# Generated by FakeRAM 2.0
VERSION 5.7 ;
BUSBITCHARS "[]" ;
PROPERTYDEFINITIONS
  MACRO width INTEGER ;
  MACRO depth INTEGER ;
  MACRO banks INTEGER ;
END PROPERTYDEFINITIONS
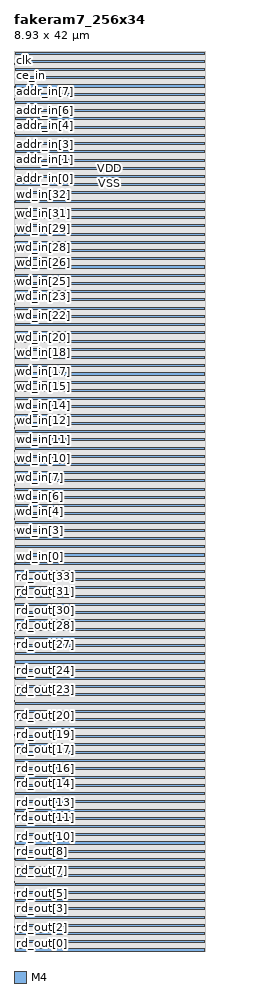
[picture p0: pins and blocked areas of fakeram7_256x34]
MACRO fakeram7_256x34
  PROPERTY width 34 ;
  PROPERTY depth 256 ;
  PROPERTY banks 2 ;
  FOREIGN fakeram7_256x34 0 0 ;
  SYMMETRY X Y R90 ;
  SIZE 8.930 BY 42.000 ;
  CLASS BLOCK ;
  PIN rd_out[0]
    DIRECTION OUTPUT ;
    USE SIGNAL ;
    SHAPE ABUTMENT ;
    PORT
      LAYER M4 ;
      RECT 0.000 0.048 0.024 0.072 ;
    END
  END rd_out[0]
  PIN rd_out[1]
    DIRECTION OUTPUT ;
    USE SIGNAL ;
    SHAPE ABUTMENT ;
    PORT
      LAYER M4 ;
      RECT 0.000 0.576 0.024 0.600 ;
    END
  END rd_out[1]
  PIN rd_out[2]
    DIRECTION OUTPUT ;
    USE SIGNAL ;
    SHAPE ABUTMENT ;
    PORT
      LAYER M4 ;
      RECT 0.000 1.104 0.024 1.128 ;
    END
  END rd_out[2]
  PIN rd_out[3]
    DIRECTION OUTPUT ;
    USE SIGNAL ;
    SHAPE ABUTMENT ;
    PORT
      LAYER M4 ;
      RECT 0.000 1.632 0.024 1.656 ;
    END
  END rd_out[3]
  PIN rd_out[4]
    DIRECTION OUTPUT ;
    USE SIGNAL ;
    SHAPE ABUTMENT ;
    PORT
      LAYER M4 ;
      RECT 0.000 2.160 0.024 2.184 ;
    END
  END rd_out[4]
  PIN rd_out[5]
    DIRECTION OUTPUT ;
    USE SIGNAL ;
    SHAPE ABUTMENT ;
    PORT
      LAYER M4 ;
      RECT 0.000 2.688 0.024 2.712 ;
    END
  END rd_out[5]
  PIN rd_out[6]
    DIRECTION OUTPUT ;
    USE SIGNAL ;
    SHAPE ABUTMENT ;
    PORT
      LAYER M4 ;
      RECT 0.000 3.216 0.024 3.240 ;
    END
  END rd_out[6]
  PIN rd_out[7]
    DIRECTION OUTPUT ;
    USE SIGNAL ;
    SHAPE ABUTMENT ;
    PORT
      LAYER M4 ;
      RECT 0.000 3.744 0.024 3.768 ;
    END
  END rd_out[7]
  PIN rd_out[8]
    DIRECTION OUTPUT ;
    USE SIGNAL ;
    SHAPE ABUTMENT ;
    PORT
      LAYER M4 ;
      RECT 0.000 4.272 0.024 4.296 ;
    END
  END rd_out[8]
  PIN rd_out[9]
    DIRECTION OUTPUT ;
    USE SIGNAL ;
    SHAPE ABUTMENT ;
    PORT
      LAYER M4 ;
      RECT 0.000 4.800 0.024 4.824 ;
    END
  END rd_out[9]
  PIN rd_out[10]
    DIRECTION OUTPUT ;
    USE SIGNAL ;
    SHAPE ABUTMENT ;
    PORT
      LAYER M4 ;
      RECT 0.000 5.328 0.024 5.352 ;
    END
  END rd_out[10]
  PIN rd_out[11]
    DIRECTION OUTPUT ;
    USE SIGNAL ;
    SHAPE ABUTMENT ;
    PORT
      LAYER M4 ;
      RECT 0.000 5.856 0.024 5.880 ;
    END
  END rd_out[11]
  PIN rd_out[12]
    DIRECTION OUTPUT ;
    USE SIGNAL ;
    SHAPE ABUTMENT ;
    PORT
      LAYER M4 ;
      RECT 0.000 6.384 0.024 6.408 ;
    END
  END rd_out[12]
  PIN rd_out[13]
    DIRECTION OUTPUT ;
    USE SIGNAL ;
    SHAPE ABUTMENT ;
    PORT
      LAYER M4 ;
      RECT 0.000 6.912 0.024 6.936 ;
    END
  END rd_out[13]
  PIN rd_out[14]
    DIRECTION OUTPUT ;
    USE SIGNAL ;
    SHAPE ABUTMENT ;
    PORT
      LAYER M4 ;
      RECT 0.000 7.440 0.024 7.464 ;
    END
  END rd_out[14]
  PIN rd_out[15]
    DIRECTION OUTPUT ;
    USE SIGNAL ;
    SHAPE ABUTMENT ;
    PORT
      LAYER M4 ;
      RECT 0.000 7.968 0.024 7.992 ;
    END
  END rd_out[15]
  PIN rd_out[16]
    DIRECTION OUTPUT ;
    USE SIGNAL ;
    SHAPE ABUTMENT ;
    PORT
      LAYER M4 ;
      RECT 0.000 8.496 0.024 8.520 ;
    END
  END rd_out[16]
  PIN rd_out[17]
    DIRECTION OUTPUT ;
    USE SIGNAL ;
    SHAPE ABUTMENT ;
    PORT
      LAYER M4 ;
      RECT 0.000 9.024 0.024 9.048 ;
    END
  END rd_out[17]
  PIN rd_out[18]
    DIRECTION OUTPUT ;
    USE SIGNAL ;
    SHAPE ABUTMENT ;
    PORT
      LAYER M4 ;
      RECT 0.000 9.552 0.024 9.576 ;
    END
  END rd_out[18]
  PIN rd_out[19]
    DIRECTION OUTPUT ;
    USE SIGNAL ;
    SHAPE ABUTMENT ;
    PORT
      LAYER M4 ;
      RECT 0.000 10.080 0.024 10.104 ;
    END
  END rd_out[19]
  PIN rd_out[20]
    DIRECTION OUTPUT ;
    USE SIGNAL ;
    SHAPE ABUTMENT ;
    PORT
      LAYER M4 ;
      RECT 0.000 10.608 0.024 10.632 ;
    END
  END rd_out[20]
  PIN rd_out[21]
    DIRECTION OUTPUT ;
    USE SIGNAL ;
    SHAPE ABUTMENT ;
    PORT
      LAYER M4 ;
      RECT 0.000 11.136 0.024 11.160 ;
    END
  END rd_out[21]
  PIN rd_out[22]
    DIRECTION OUTPUT ;
    USE SIGNAL ;
    SHAPE ABUTMENT ;
    PORT
      LAYER M4 ;
      RECT 0.000 11.664 0.024 11.688 ;
    END
  END rd_out[22]
  PIN rd_out[23]
    DIRECTION OUTPUT ;
    USE SIGNAL ;
    SHAPE ABUTMENT ;
    PORT
      LAYER M4 ;
      RECT 0.000 12.192 0.024 12.216 ;
    END
  END rd_out[23]
  PIN rd_out[24]
    DIRECTION OUTPUT ;
    USE SIGNAL ;
    SHAPE ABUTMENT ;
    PORT
      LAYER M4 ;
      RECT 0.000 12.720 0.024 12.744 ;
    END
  END rd_out[24]
  PIN rd_out[25]
    DIRECTION OUTPUT ;
    USE SIGNAL ;
    SHAPE ABUTMENT ;
    PORT
      LAYER M4 ;
      RECT 0.000 13.248 0.024 13.272 ;
    END
  END rd_out[25]
  PIN rd_out[26]
    DIRECTION OUTPUT ;
    USE SIGNAL ;
    SHAPE ABUTMENT ;
    PORT
      LAYER M4 ;
      RECT 0.000 13.776 0.024 13.800 ;
    END
  END rd_out[26]
  PIN rd_out[27]
    DIRECTION OUTPUT ;
    USE SIGNAL ;
    SHAPE ABUTMENT ;
    PORT
      LAYER M4 ;
      RECT 0.000 14.304 0.024 14.328 ;
    END
  END rd_out[27]
  PIN rd_out[28]
    DIRECTION OUTPUT ;
    USE SIGNAL ;
    SHAPE ABUTMENT ;
    PORT
      LAYER M4 ;
      RECT 0.000 14.832 0.024 14.856 ;
    END
  END rd_out[28]
  PIN rd_out[29]
    DIRECTION OUTPUT ;
    USE SIGNAL ;
    SHAPE ABUTMENT ;
    PORT
      LAYER M4 ;
      RECT 0.000 15.360 0.024 15.384 ;
    END
  END rd_out[29]
  PIN rd_out[30]
    DIRECTION OUTPUT ;
    USE SIGNAL ;
    SHAPE ABUTMENT ;
    PORT
      LAYER M4 ;
      RECT 0.000 15.888 0.024 15.912 ;
    END
  END rd_out[30]
  PIN rd_out[31]
    DIRECTION OUTPUT ;
    USE SIGNAL ;
    SHAPE ABUTMENT ;
    PORT
      LAYER M4 ;
      RECT 0.000 16.416 0.024 16.440 ;
    END
  END rd_out[31]
  PIN rd_out[32]
    DIRECTION OUTPUT ;
    USE SIGNAL ;
    SHAPE ABUTMENT ;
    PORT
      LAYER M4 ;
      RECT 0.000 16.944 0.024 16.968 ;
    END
  END rd_out[32]
  PIN rd_out[33]
    DIRECTION OUTPUT ;
    USE SIGNAL ;
    SHAPE ABUTMENT ;
    PORT
      LAYER M4 ;
      RECT 0.000 17.472 0.024 17.496 ;
    END
  END rd_out[33]
  PIN wd_in[0]
    DIRECTION INPUT ;
    USE SIGNAL ;
    SHAPE ABUTMENT ;
    PORT
      LAYER M4 ;
      RECT 0.000 18.048 0.024 18.072 ;
    END
  END wd_in[0]
  PIN wd_in[1]
    DIRECTION INPUT ;
    USE SIGNAL ;
    SHAPE ABUTMENT ;
    PORT
      LAYER M4 ;
      RECT 0.000 18.576 0.024 18.600 ;
    END
  END wd_in[1]
  PIN wd_in[2]
    DIRECTION INPUT ;
    USE SIGNAL ;
    SHAPE ABUTMENT ;
    PORT
      LAYER M4 ;
      RECT 0.000 19.104 0.024 19.128 ;
    END
  END wd_in[2]
  PIN wd_in[3]
    DIRECTION INPUT ;
    USE SIGNAL ;
    SHAPE ABUTMENT ;
    PORT
      LAYER M4 ;
      RECT 0.000 19.632 0.024 19.656 ;
    END
  END wd_in[3]
  PIN wd_in[4]
    DIRECTION INPUT ;
    USE SIGNAL ;
    SHAPE ABUTMENT ;
    PORT
      LAYER M4 ;
      RECT 0.000 20.160 0.024 20.184 ;
    END
  END wd_in[4]
  PIN wd_in[5]
    DIRECTION INPUT ;
    USE SIGNAL ;
    SHAPE ABUTMENT ;
    PORT
      LAYER M4 ;
      RECT 0.000 20.688 0.024 20.712 ;
    END
  END wd_in[5]
  PIN wd_in[6]
    DIRECTION INPUT ;
    USE SIGNAL ;
    SHAPE ABUTMENT ;
    PORT
      LAYER M4 ;
      RECT 0.000 21.216 0.024 21.240 ;
    END
  END wd_in[6]
  PIN wd_in[7]
    DIRECTION INPUT ;
    USE SIGNAL ;
    SHAPE ABUTMENT ;
    PORT
      LAYER M4 ;
      RECT 0.000 21.744 0.024 21.768 ;
    END
  END wd_in[7]
  PIN wd_in[8]
    DIRECTION INPUT ;
    USE SIGNAL ;
    SHAPE ABUTMENT ;
    PORT
      LAYER M4 ;
      RECT 0.000 22.272 0.024 22.296 ;
    END
  END wd_in[8]
  PIN wd_in[9]
    DIRECTION INPUT ;
    USE SIGNAL ;
    SHAPE ABUTMENT ;
    PORT
      LAYER M4 ;
      RECT 0.000 22.800 0.024 22.824 ;
    END
  END wd_in[9]
  PIN wd_in[10]
    DIRECTION INPUT ;
    USE SIGNAL ;
    SHAPE ABUTMENT ;
    PORT
      LAYER M4 ;
      RECT 0.000 23.328 0.024 23.352 ;
    END
  END wd_in[10]
  PIN wd_in[11]
    DIRECTION INPUT ;
    USE SIGNAL ;
    SHAPE ABUTMENT ;
    PORT
      LAYER M4 ;
      RECT 0.000 23.856 0.024 23.880 ;
    END
  END wd_in[11]
  PIN wd_in[12]
    DIRECTION INPUT ;
    USE SIGNAL ;
    SHAPE ABUTMENT ;
    PORT
      LAYER M4 ;
      RECT 0.000 24.384 0.024 24.408 ;
    END
  END wd_in[12]
  PIN wd_in[13]
    DIRECTION INPUT ;
    USE SIGNAL ;
    SHAPE ABUTMENT ;
    PORT
      LAYER M4 ;
      RECT 0.000 24.912 0.024 24.936 ;
    END
  END wd_in[13]
  PIN wd_in[14]
    DIRECTION INPUT ;
    USE SIGNAL ;
    SHAPE ABUTMENT ;
    PORT
      LAYER M4 ;
      RECT 0.000 25.440 0.024 25.464 ;
    END
  END wd_in[14]
  PIN wd_in[15]
    DIRECTION INPUT ;
    USE SIGNAL ;
    SHAPE ABUTMENT ;
    PORT
      LAYER M4 ;
      RECT 0.000 25.968 0.024 25.992 ;
    END
  END wd_in[15]
  PIN wd_in[16]
    DIRECTION INPUT ;
    USE SIGNAL ;
    SHAPE ABUTMENT ;
    PORT
      LAYER M4 ;
      RECT 0.000 26.496 0.024 26.520 ;
    END
  END wd_in[16]
  PIN wd_in[17]
    DIRECTION INPUT ;
    USE SIGNAL ;
    SHAPE ABUTMENT ;
    PORT
      LAYER M4 ;
      RECT 0.000 27.024 0.024 27.048 ;
    END
  END wd_in[17]
  PIN wd_in[18]
    DIRECTION INPUT ;
    USE SIGNAL ;
    SHAPE ABUTMENT ;
    PORT
      LAYER M4 ;
      RECT 0.000 27.552 0.024 27.576 ;
    END
  END wd_in[18]
  PIN wd_in[19]
    DIRECTION INPUT ;
    USE SIGNAL ;
    SHAPE ABUTMENT ;
    PORT
      LAYER M4 ;
      RECT 0.000 28.080 0.024 28.104 ;
    END
  END wd_in[19]
  PIN wd_in[20]
    DIRECTION INPUT ;
    USE SIGNAL ;
    SHAPE ABUTMENT ;
    PORT
      LAYER M4 ;
      RECT 0.000 28.608 0.024 28.632 ;
    END
  END wd_in[20]
  PIN wd_in[21]
    DIRECTION INPUT ;
    USE SIGNAL ;
    SHAPE ABUTMENT ;
    PORT
      LAYER M4 ;
      RECT 0.000 29.136 0.024 29.160 ;
    END
  END wd_in[21]
  PIN wd_in[22]
    DIRECTION INPUT ;
    USE SIGNAL ;
    SHAPE ABUTMENT ;
    PORT
      LAYER M4 ;
      RECT 0.000 29.664 0.024 29.688 ;
    END
  END wd_in[22]
  PIN wd_in[23]
    DIRECTION INPUT ;
    USE SIGNAL ;
    SHAPE ABUTMENT ;
    PORT
      LAYER M4 ;
      RECT 0.000 30.192 0.024 30.216 ;
    END
  END wd_in[23]
  PIN wd_in[24]
    DIRECTION INPUT ;
    USE SIGNAL ;
    SHAPE ABUTMENT ;
    PORT
      LAYER M4 ;
      RECT 0.000 30.720 0.024 30.744 ;
    END
  END wd_in[24]
  PIN wd_in[25]
    DIRECTION INPUT ;
    USE SIGNAL ;
    SHAPE ABUTMENT ;
    PORT
      LAYER M4 ;
      RECT 0.000 31.248 0.024 31.272 ;
    END
  END wd_in[25]
  PIN wd_in[26]
    DIRECTION INPUT ;
    USE SIGNAL ;
    SHAPE ABUTMENT ;
    PORT
      LAYER M4 ;
      RECT 0.000 31.776 0.024 31.800 ;
    END
  END wd_in[26]
  PIN wd_in[27]
    DIRECTION INPUT ;
    USE SIGNAL ;
    SHAPE ABUTMENT ;
    PORT
      LAYER M4 ;
      RECT 0.000 32.304 0.024 32.328 ;
    END
  END wd_in[27]
  PIN wd_in[28]
    DIRECTION INPUT ;
    USE SIGNAL ;
    SHAPE ABUTMENT ;
    PORT
      LAYER M4 ;
      RECT 0.000 32.832 0.024 32.856 ;
    END
  END wd_in[28]
  PIN wd_in[29]
    DIRECTION INPUT ;
    USE SIGNAL ;
    SHAPE ABUTMENT ;
    PORT
      LAYER M4 ;
      RECT 0.000 33.360 0.024 33.384 ;
    END
  END wd_in[29]
  PIN wd_in[30]
    DIRECTION INPUT ;
    USE SIGNAL ;
    SHAPE ABUTMENT ;
    PORT
      LAYER M4 ;
      RECT 0.000 33.888 0.024 33.912 ;
    END
  END wd_in[30]
  PIN wd_in[31]
    DIRECTION INPUT ;
    USE SIGNAL ;
    SHAPE ABUTMENT ;
    PORT
      LAYER M4 ;
      RECT 0.000 34.416 0.024 34.440 ;
    END
  END wd_in[31]
  PIN wd_in[32]
    DIRECTION INPUT ;
    USE SIGNAL ;
    SHAPE ABUTMENT ;
    PORT
      LAYER M4 ;
      RECT 0.000 34.944 0.024 34.968 ;
    END
  END wd_in[32]
  PIN wd_in[33]
    DIRECTION INPUT ;
    USE SIGNAL ;
    SHAPE ABUTMENT ;
    PORT
      LAYER M4 ;
      RECT 0.000 35.472 0.024 35.496 ;
    END
  END wd_in[33]
  PIN addr_in[0]
    DIRECTION INPUT ;
    USE SIGNAL ;
    SHAPE ABUTMENT ;
    PORT
      LAYER M4 ;
      RECT 0.000 36.048 0.024 36.072 ;
    END
  END addr_in[0]
  PIN addr_in[1]
    DIRECTION INPUT ;
    USE SIGNAL ;
    SHAPE ABUTMENT ;
    PORT
      LAYER M4 ;
      RECT 0.000 36.576 0.024 36.600 ;
    END
  END addr_in[1]
  PIN addr_in[2]
    DIRECTION INPUT ;
    USE SIGNAL ;
    SHAPE ABUTMENT ;
    PORT
      LAYER M4 ;
      RECT 0.000 37.104 0.024 37.128 ;
    END
  END addr_in[2]
  PIN addr_in[3]
    DIRECTION INPUT ;
    USE SIGNAL ;
    SHAPE ABUTMENT ;
    PORT
      LAYER M4 ;
      RECT 0.000 37.632 0.024 37.656 ;
    END
  END addr_in[3]
  PIN addr_in[4]
    DIRECTION INPUT ;
    USE SIGNAL ;
    SHAPE ABUTMENT ;
    PORT
      LAYER M4 ;
      RECT 0.000 38.160 0.024 38.184 ;
    END
  END addr_in[4]
  PIN addr_in[5]
    DIRECTION INPUT ;
    USE SIGNAL ;
    SHAPE ABUTMENT ;
    PORT
      LAYER M4 ;
      RECT 0.000 38.688 0.024 38.712 ;
    END
  END addr_in[5]
  PIN addr_in[6]
    DIRECTION INPUT ;
    USE SIGNAL ;
    SHAPE ABUTMENT ;
    PORT
      LAYER M4 ;
      RECT 0.000 39.216 0.024 39.240 ;
    END
  END addr_in[6]
  PIN addr_in[7]
    DIRECTION INPUT ;
    USE SIGNAL ;
    SHAPE ABUTMENT ;
    PORT
      LAYER M4 ;
      RECT 0.000 39.744 0.024 39.768 ;
    END
  END addr_in[7]
  PIN we_in
    DIRECTION INPUT ;
    USE SIGNAL ;
    SHAPE ABUTMENT ;
    PORT
      LAYER M4 ;
      RECT 0.000 40.320 0.024 40.344 ;
    END
  END we_in
  PIN ce_in
    DIRECTION INPUT ;
    USE SIGNAL ;
    SHAPE ABUTMENT ;
    PORT
      LAYER M4 ;
      RECT 0.000 40.848 0.024 40.872 ;
    END
  END ce_in
  PIN clk
    DIRECTION INPUT ;
    USE SIGNAL ;
    SHAPE ABUTMENT ;
    PORT
      LAYER M4 ;
      RECT 0.000 41.376 0.024 41.400 ;
    END
  END clk
  PIN VSS
    DIRECTION INOUT ;
    USE GROUND ;
    PORT
      LAYER M4 ;
      RECT 0.048 0.000 8.882 0.096 ;
      RECT 0.048 0.768 8.882 0.864 ;
      RECT 0.048 1.536 8.882 1.632 ;
      RECT 0.048 2.304 8.882 2.400 ;
      RECT 0.048 3.072 8.882 3.168 ;
      RECT 0.048 3.840 8.882 3.936 ;
      RECT 0.048 4.608 8.882 4.704 ;
      RECT 0.048 5.376 8.882 5.472 ;
      RECT 0.048 6.144 8.882 6.240 ;
      RECT 0.048 6.912 8.882 7.008 ;
      RECT 0.048 7.680 8.882 7.776 ;
      RECT 0.048 8.448 8.882 8.544 ;
      RECT 0.048 9.216 8.882 9.312 ;
      RECT 0.048 9.984 8.882 10.080 ;
      RECT 0.048 10.752 8.882 10.848 ;
      RECT 0.048 11.520 8.882 11.616 ;
      RECT 0.048 12.288 8.882 12.384 ;
      RECT 0.048 13.056 8.882 13.152 ;
      RECT 0.048 13.824 8.882 13.920 ;
      RECT 0.048 14.592 8.882 14.688 ;
      RECT 0.048 15.360 8.882 15.456 ;
      RECT 0.048 16.128 8.882 16.224 ;
      RECT 0.048 16.896 8.882 16.992 ;
      RECT 0.048 17.664 8.882 17.760 ;
      RECT 0.048 18.432 8.882 18.528 ;
      RECT 0.048 19.200 8.882 19.296 ;
      RECT 0.048 19.968 8.882 20.064 ;
      RECT 0.048 20.736 8.882 20.832 ;
      RECT 0.048 21.504 8.882 21.600 ;
      RECT 0.048 22.272 8.882 22.368 ;
      RECT 0.048 23.040 8.882 23.136 ;
      RECT 0.048 23.808 8.882 23.904 ;
      RECT 0.048 24.576 8.882 24.672 ;
      RECT 0.048 25.344 8.882 25.440 ;
      RECT 0.048 26.112 8.882 26.208 ;
      RECT 0.048 26.880 8.882 26.976 ;
      RECT 0.048 27.648 8.882 27.744 ;
      RECT 0.048 28.416 8.882 28.512 ;
      RECT 0.048 29.184 8.882 29.280 ;
      RECT 0.048 29.952 8.882 30.048 ;
      RECT 0.048 30.720 8.882 30.816 ;
      RECT 0.048 31.488 8.882 31.584 ;
      RECT 0.048 32.256 8.882 32.352 ;
      RECT 0.048 33.024 8.882 33.120 ;
      RECT 0.048 33.792 8.882 33.888 ;
      RECT 0.048 34.560 8.882 34.656 ;
      RECT 0.048 35.328 8.882 35.424 ;
      RECT 0.048 36.096 8.882 36.192 ;
      RECT 0.048 36.864 8.882 36.960 ;
      RECT 0.048 37.632 8.882 37.728 ;
      RECT 0.048 38.400 8.882 38.496 ;
      RECT 0.048 39.168 8.882 39.264 ;
      RECT 0.048 39.936 8.882 40.032 ;
      RECT 0.048 40.704 8.882 40.800 ;
      RECT 0.048 41.472 8.882 41.568 ;
    END
  END VSS
  PIN VDD
    DIRECTION INOUT ;
    USE POWER ;
    PORT
      LAYER M4 ;
      RECT 0.048 0.384 8.882 0.480 ;
      RECT 0.048 1.152 8.882 1.248 ;
      RECT 0.048 1.920 8.882 2.016 ;
      RECT 0.048 2.688 8.882 2.784 ;
      RECT 0.048 3.456 8.882 3.552 ;
      RECT 0.048 4.224 8.882 4.320 ;
      RECT 0.048 4.992 8.882 5.088 ;
      RECT 0.048 5.760 8.882 5.856 ;
      RECT 0.048 6.528 8.882 6.624 ;
      RECT 0.048 7.296 8.882 7.392 ;
      RECT 0.048 8.064 8.882 8.160 ;
      RECT 0.048 8.832 8.882 8.928 ;
      RECT 0.048 9.600 8.882 9.696 ;
      RECT 0.048 10.368 8.882 10.464 ;
      RECT 0.048 11.136 8.882 11.232 ;
      RECT 0.048 11.904 8.882 12.000 ;
      RECT 0.048 12.672 8.882 12.768 ;
      RECT 0.048 13.440 8.882 13.536 ;
      RECT 0.048 14.208 8.882 14.304 ;
      RECT 0.048 14.976 8.882 15.072 ;
      RECT 0.048 15.744 8.882 15.840 ;
      RECT 0.048 16.512 8.882 16.608 ;
      RECT 0.048 17.280 8.882 17.376 ;
      RECT 0.048 18.048 8.882 18.144 ;
      RECT 0.048 18.816 8.882 18.912 ;
      RECT 0.048 19.584 8.882 19.680 ;
      RECT 0.048 20.352 8.882 20.448 ;
      RECT 0.048 21.120 8.882 21.216 ;
      RECT 0.048 21.888 8.882 21.984 ;
      RECT 0.048 22.656 8.882 22.752 ;
      RECT 0.048 23.424 8.882 23.520 ;
      RECT 0.048 24.192 8.882 24.288 ;
      RECT 0.048 24.960 8.882 25.056 ;
      RECT 0.048 25.728 8.882 25.824 ;
      RECT 0.048 26.496 8.882 26.592 ;
      RECT 0.048 27.264 8.882 27.360 ;
      RECT 0.048 28.032 8.882 28.128 ;
      RECT 0.048 28.800 8.882 28.896 ;
      RECT 0.048 29.568 8.882 29.664 ;
      RECT 0.048 30.336 8.882 30.432 ;
      RECT 0.048 31.104 8.882 31.200 ;
      RECT 0.048 31.872 8.882 31.968 ;
      RECT 0.048 32.640 8.882 32.736 ;
      RECT 0.048 33.408 8.882 33.504 ;
      RECT 0.048 34.176 8.882 34.272 ;
      RECT 0.048 34.944 8.882 35.040 ;
      RECT 0.048 35.712 8.882 35.808 ;
      RECT 0.048 36.480 8.882 36.576 ;
      RECT 0.048 37.248 8.882 37.344 ;
      RECT 0.048 38.016 8.882 38.112 ;
      RECT 0.048 38.784 8.882 38.880 ;
      RECT 0.048 39.552 8.882 39.648 ;
      RECT 0.048 40.320 8.882 40.416 ;
      RECT 0.048 41.088 8.882 41.184 ;
      RECT 0.048 41.856 8.882 41.952 ;
    END
  END VDD
  OBS
    LAYER M1 ;
    RECT 0 0 8.930 42.000 ;
    LAYER M2 ;
    RECT 0 0 8.930 42.000 ;
    LAYER M3 ;
    RECT 0 0 8.930 42.000 ;
    LAYER M4 ;
    RECT 0 0 8.930 42.000 ;
  END
END fakeram7_256x34

END LIBRARY
